VERSION 5.7 ;
  NOWIREEXTENSIONATPIN ON ;
  DIVIDERCHAR "/" ;
  BUSBITCHARS "[]" ;
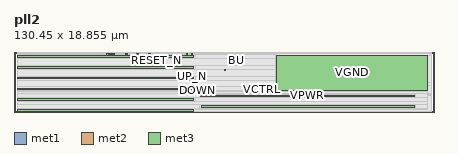
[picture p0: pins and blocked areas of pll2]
MACRO pll2
  CLASS BLOCK ;
  FOREIGN pll2 ;
  ORIGIN 0.000 0.000 ;
  SIZE 130.450 BY 18.855 ;
  PIN BU
    ANTENNAGATEAREA 9.721000 ;
    ANTENNADIFFAREA 0.650000 ;
    PORT
      LAYER met1 ;
        RECT 68.940 17.220 69.325 17.530 ;
    END
  END BU
  PIN BD
    ANTENNAGATEAREA 10.682099 ;
    ANTENNADIFFAREA 0.447500 ;
    PORT
      LAYER met1 ;
        RECT 65.350 13.005 65.745 13.320 ;
    END
  END BD
  PIN VCTRL
    ANTENNAGATEAREA 1.241700 ;
    ANTENNADIFFAREA 2.143000 ;
    PORT
      LAYER met2 ;
        RECT 76.935 6.060 77.205 7.910 ;
    END
  END VCTRL
  PIN COUNT_0
    ANTENNAGATEAREA 0.540000 ;
    PORT
      LAYER met2 ;
        RECT 28.865 17.695 29.235 18.075 ;
    END
  END COUNT_0
  PIN COUNT_1
    ANTENNAGATEAREA 0.540000 ;
    PORT
      LAYER met2 ;
        RECT 29.690 17.685 30.060 18.065 ;
    END
  END COUNT_1
  PIN COUNT_3
    ANTENNAGATEAREA 0.540000 ;
    PORT
      LAYER met2 ;
        RECT 30.320 17.685 30.690 18.065 ;
    END
  END COUNT_3
  PIN COUNT_2
    ANTENNAGATEAREA 0.540000 ;
    PORT
      LAYER met2 ;
        RECT 30.920 17.685 31.290 18.065 ;
    END
  END COUNT_2
  PIN RESET_N
    ANTENNAGATEAREA 0.279000 ;
    PORT
      LAYER met2 ;
        RECT 43.965 17.780 44.325 18.010 ;
    END
  END RESET_N
  PIN CLK
    ANTENNADIFFAREA 0.924000 ;
    PORT
      LAYER met2 ;
        RECT 53.455 17.760 53.940 18.020 ;
    END
  END CLK
  PIN RESET_OUT_N
    ANTENNADIFFAREA 0.543200 ;
    PORT
      LAYER met2 ;
        RECT 55.035 17.785 55.395 18.015 ;
    END
  END RESET_OUT_N
  PIN UP_N
    ANTENNAGATEAREA 0.252000 ;
    ANTENNADIFFAREA 0.541300 ;
    PORT
      LAYER met2 ;
        RECT 55.090 8.535 55.350 8.865 ;
    END
  END UP_N
  PIN DOWN
    ANTENNAGATEAREA 0.378000 ;
    ANTENNADIFFAREA 0.604500 ;
    PORT
      LAYER met2 ;
        RECT 56.795 6.435 57.055 6.765 ;
    END
  END DOWN
  PIN DOWN_N
    ANTENNAGATEAREA 0.252000 ;
    ANTENNADIFFAREA 0.541300 ;
    PORT
      LAYER met2 ;
        RECT 55.085 5.625 55.355 5.955 ;
    END
  END DOWN_N
  PIN LOCALCLK
    ANTENNAGATEAREA 0.558000 ;
    ANTENNADIFFAREA 0.541300 ;
    PORT
      LAYER met2 ;
        RECT 52.040 5.385 52.485 5.715 ;
    END
  END LOCALCLK
  PIN UP
    ANTENNAGATEAREA 0.378000 ;
    ANTENNADIFFAREA 0.604500 ;
    PORT
      LAYER met2 ;
        RECT 56.795 8.425 57.065 8.815 ;
    END
  END UP
  PIN REFCLK
    ANTENNAGATEAREA 0.231000 ;
    PORT
      LAYER met2 ;
        RECT 41.790 17.770 42.275 18.030 ;
    END
  END REFCLK
  PIN COUNT_OVER
    ANTENNAGATEAREA 0.208500 ;
    ANTENNADIFFAREA 0.710200 ;
    PORT
      LAYER met2 ;
        RECT 38.135 17.770 38.620 18.030 ;
    END
  END COUNT_OVER
  PIN LOCKABLE
    ANTENNAGATEAREA 1.456500 ;
    ANTENNADIFFAREA 0.541300 ;
    PORT
      LAYER met2 ;
        RECT 34.780 17.770 35.265 18.030 ;
    END
  END LOCKABLE
  PIN VGND
    USE GROUND ;
    PORT
      LAYER met3 ;
        RECT 1.185 0.300 55.905 0.780 ;
    END
    PORT
      LAYER met3 ;
        RECT 1.185 6.960 55.905 7.440 ;
    END
    PORT
      LAYER met3 ;
        RECT 1.185 13.625 55.905 14.105 ;
    END
    PORT
      LAYER met3 ;
        RECT 58.105 1.430 124.280 1.920 ;
    END
    PORT
      LAYER met3 ;
        RECT 81.525 6.645 128.375 17.695 ;
    END
  END VGND
  PIN VPWR
    USE POWER ;
    PORT
      LAYER met3 ;
        RECT 1.185 16.960 55.905 17.440 ;
    END
    PORT
      LAYER met3 ;
        RECT 1.185 10.295 55.905 10.775 ;
    END
    PORT
      LAYER met3 ;
        RECT 1.185 3.635 55.905 4.115 ;
    END
    PORT
      LAYER met3 ;
        RECT 58.065 4.760 124.240 5.250 ;
    END
  END VPWR
  OBS
      LAYER nwell ;
        RECT 0.995 0.545 128.980 18.210 ;
      LAYER li1 ;
        RECT 1.185 0.460 129.770 18.340 ;
      LAYER met1 ;
        RECT 1.185 17.810 129.800 18.245 ;
        RECT 1.185 16.940 68.660 17.810 ;
        RECT 69.605 16.940 129.800 17.810 ;
        RECT 1.185 13.600 129.800 16.940 ;
        RECT 1.185 12.725 65.070 13.600 ;
        RECT 66.025 12.725 129.800 13.600 ;
        RECT 1.185 0.300 129.800 12.725 ;
      LAYER met2 ;
        RECT 1.185 17.415 28.585 18.290 ;
        RECT 31.570 17.490 34.500 18.290 ;
        RECT 35.545 17.490 37.855 18.290 ;
        RECT 38.900 17.490 41.510 18.290 ;
        RECT 42.555 17.500 43.685 18.290 ;
        RECT 44.605 17.500 53.175 18.290 ;
        RECT 42.555 17.490 53.175 17.500 ;
        RECT 31.570 17.480 53.175 17.490 ;
        RECT 54.220 17.505 54.755 18.290 ;
        RECT 55.675 17.505 129.770 18.290 ;
        RECT 54.220 17.480 129.770 17.505 ;
        RECT 1.185 17.405 29.410 17.415 ;
        RECT 31.570 17.405 129.770 17.480 ;
        RECT 1.185 9.145 129.770 17.405 ;
        RECT 1.185 8.255 54.810 9.145 ;
        RECT 55.630 9.095 129.770 9.145 ;
        RECT 55.630 8.255 56.515 9.095 ;
        RECT 1.185 8.145 56.515 8.255 ;
        RECT 57.345 8.190 129.770 9.095 ;
        RECT 57.345 8.145 76.655 8.190 ;
        RECT 1.185 7.045 76.655 8.145 ;
        RECT 1.185 6.235 56.515 7.045 ;
        RECT 1.185 5.995 54.805 6.235 ;
        RECT 1.185 5.105 51.760 5.995 ;
        RECT 52.765 5.345 54.805 5.995 ;
        RECT 55.635 6.155 56.515 6.235 ;
        RECT 57.335 6.155 76.655 7.045 ;
        RECT 55.635 5.780 76.655 6.155 ;
        RECT 77.485 5.780 129.770 8.190 ;
        RECT 55.635 5.345 129.770 5.780 ;
        RECT 52.765 5.105 129.770 5.345 ;
        RECT 1.185 0.300 129.770 5.105 ;
      LAYER met3 ;
        RECT 1.185 18.095 128.325 18.170 ;
        RECT 1.185 17.840 81.125 18.095 ;
        RECT 56.305 16.560 81.125 17.840 ;
        RECT 1.185 14.505 81.125 16.560 ;
        RECT 56.305 13.225 81.125 14.505 ;
        RECT 1.185 11.175 81.125 13.225 ;
        RECT 56.305 9.895 81.125 11.175 ;
        RECT 1.185 7.840 81.125 9.895 ;
        RECT 56.305 6.560 81.125 7.840 ;
        RECT 1.185 6.245 81.125 6.560 ;
        RECT 1.185 5.650 128.325 6.245 ;
        RECT 1.185 4.515 57.665 5.650 ;
        RECT 56.305 4.360 57.665 4.515 ;
        RECT 124.640 4.360 128.325 5.650 ;
        RECT 56.305 3.235 128.325 4.360 ;
        RECT 1.185 2.320 128.325 3.235 ;
        RECT 1.185 1.180 57.705 2.320 ;
        RECT 56.305 1.030 57.705 1.180 ;
        RECT 124.680 1.030 128.325 2.320 ;
        RECT 56.305 0.780 128.325 1.030 ;
  END
END pll2
END LIBRARY

